VERSION 5.8 ;
BUSBITCHARS "[]" ;
DIVIDERCHAR "/" ;
CLEARANCEMEASURE EUCLIDEAN ;

SITE coresite_DH_P
    SIZE 0.0450 BY 0.2880 ;
    CLASS CORE ;
    SYMMETRY X Y ;
END coresite_DH_P

SITE coresite_DH_N
    SIZE 0.0450 BY 0.2880 ;
    CLASS CORE ;
    SYMMETRY X Y ;
END coresite_DH_N

SITE coresite
    SIZE 0.0450 BY 0.1440 ;
    CLASS CORE ;
    SYMMETRY X Y ;
END coresite

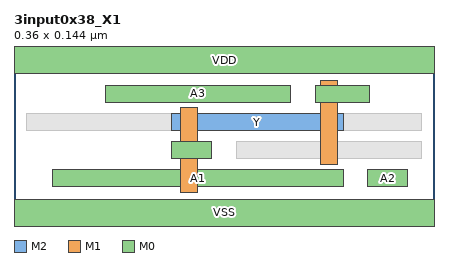
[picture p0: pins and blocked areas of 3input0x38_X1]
MACRO 3input0x38_X1
  CLASS CORE ;
  ORIGIN 0 0 ;
  FOREIGN 3input0x38_X1 0 0 ;
  SIZE 0.3600 BY 0.1440 ;
  SYMMETRY X Y ;
  SITE coresite ;
  PIN Y
    DIRECTION OUTPUT ;
    USE SIGNAL ;
    PORT
      LAYER M2 ;
        RECT 0.1350 0.0910 0.2820 0.0770 ;
      LAYER M1 ;
        RECT 0.1425 0.0960 0.1575 0.0240 ;
        RECT 0.2625 0.1200 0.2775 0.0480 ;
      LAYER M0 ;
        RECT 0.1350 0.0670 0.1695 0.0530 ;
        RECT 0.2580 0.1150 0.3045 0.1010 ;
    END
  END Y
  PIN A1
    DIRECTION INPUT ;
    USE SIGNAL ;
    PORT
      LAYER M0 ;
        RECT 0.0330 0.0430 0.2820 0.0290 ;
    END
  END A1
  PIN A2
    DIRECTION INPUT ;
    USE SIGNAL ;
    PORT
      LAYER M0 ;
        RECT 0.3030 0.0430 0.3375 0.0290 ;
    END
  END A2
  PIN A3
    DIRECTION INPUT ;
    USE SIGNAL ;
    PORT
      LAYER M0 ;
        RECT 0.0780 0.1150 0.2370 0.1010 ;
    END
  END A3
  PIN VDD
    DIRECTION INOUT ;
    USE POWER ;
    SHAPE ABUTMENT ;
    PORT
      LAYER M0 ;
        RECT 0.0000 0.1260 0.3600 0.1620 ;
    END
  END VDD
  PIN VSS
    DIRECTION INOUT ;
    USE GROUND ;
    SHAPE ABUTMENT ;
    PORT
      LAYER M0 ;
        RECT 0.0000 -0.0180 0.3600 0.0180 ;
    END
  END VSS
  OBS
      LAYER V1 ;
        RECT 0.1430 0.0770 0.1570 0.0910 ;
        RECT 0.2630 0.0770 0.2770 0.0910 ;
      LAYER V0 ;
        RECT 0.1430 0.0530 0.1570 0.0670 ;
        RECT 0.2630 0.1010 0.2770 0.1150 ;
      LAYER M0 ;
        RECT 0.1905 0.0530 0.3495 0.0670 ;
        RECT 0.0105 0.0770 0.1920 0.0910 ;
        RECT 0.2355 0.0770 0.3495 0.0910 ;
  END
END 3input0x38_X1

END LIBRARY
